VERSION 5.7 ;
BUSBITCHARS "[]" ;
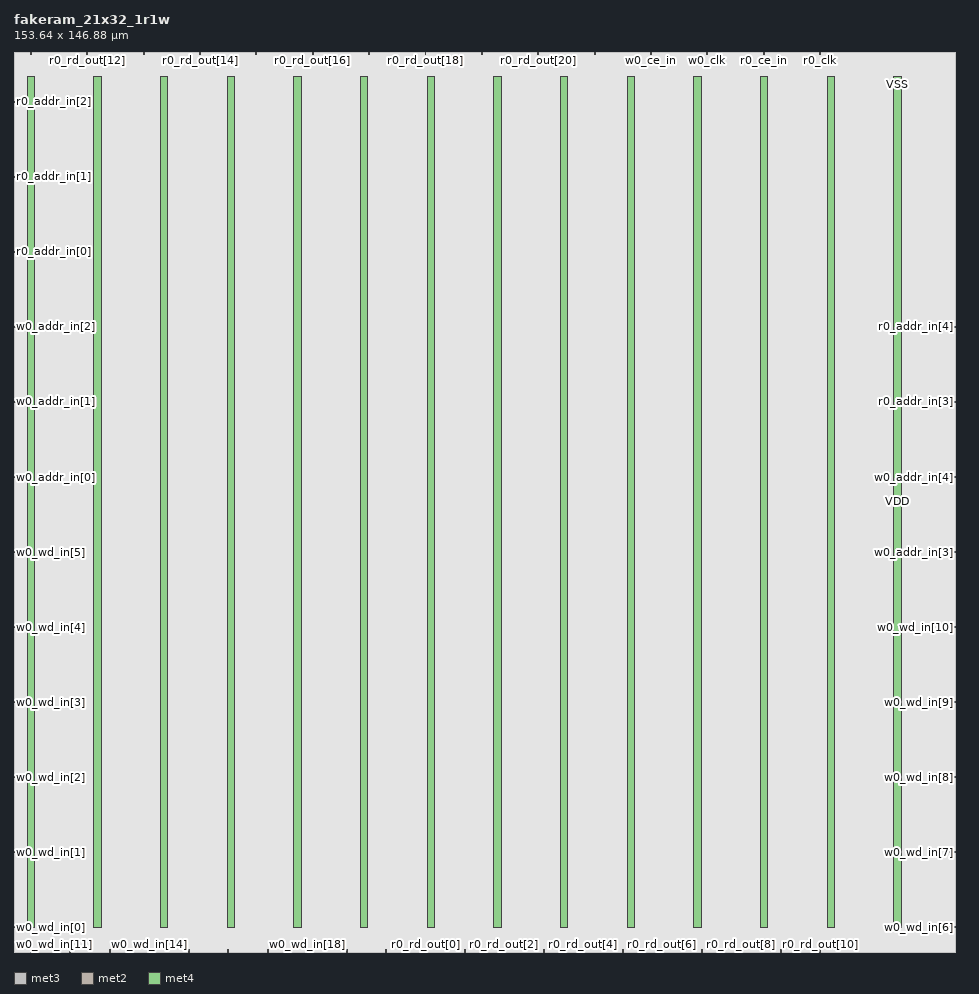
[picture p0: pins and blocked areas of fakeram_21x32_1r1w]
MACRO fakeram_21x32_1r1w
  FOREIGN fakeram_21x32_1r1w 0 0 ;
  SYMMETRY X Y R90 ;
  SIZE 153.640 BY 146.880 ;
  CLASS BLOCK ;
  PIN w0_wd_in[0]
    DIRECTION INPUT ;
    USE SIGNAL ;
    SHAPE ABUTMENT ;
    PORT
      LAYER met3 ;
      RECT 0.000 3.930 0.900 4.230 ;
    END
  END w0_wd_in[0]
  PIN w0_wd_in[1]
    DIRECTION INPUT ;
    USE SIGNAL ;
    SHAPE ABUTMENT ;
    PORT
      LAYER met3 ;
      RECT 0.000 16.170 0.900 16.470 ;
    END
  END w0_wd_in[1]
  PIN w0_wd_in[2]
    DIRECTION INPUT ;
    USE SIGNAL ;
    SHAPE ABUTMENT ;
    PORT
      LAYER met3 ;
      RECT 0.000 28.410 0.900 28.710 ;
    END
  END w0_wd_in[2]
  PIN w0_wd_in[3]
    DIRECTION INPUT ;
    USE SIGNAL ;
    SHAPE ABUTMENT ;
    PORT
      LAYER met3 ;
      RECT 0.000 40.650 0.900 40.950 ;
    END
  END w0_wd_in[3]
  PIN w0_wd_in[4]
    DIRECTION INPUT ;
    USE SIGNAL ;
    SHAPE ABUTMENT ;
    PORT
      LAYER met3 ;
      RECT 0.000 52.890 0.900 53.190 ;
    END
  END w0_wd_in[4]
  PIN w0_wd_in[5]
    DIRECTION INPUT ;
    USE SIGNAL ;
    SHAPE ABUTMENT ;
    PORT
      LAYER met3 ;
      RECT 0.000 65.130 0.900 65.430 ;
    END
  END w0_wd_in[5]
  PIN w0_wd_in[6]
    DIRECTION INPUT ;
    USE SIGNAL ;
    SHAPE ABUTMENT ;
    PORT
      LAYER met3 ;
      RECT 152.740 3.930 153.640 4.230 ;
    END
  END w0_wd_in[6]
  PIN w0_wd_in[7]
    DIRECTION INPUT ;
    USE SIGNAL ;
    SHAPE ABUTMENT ;
    PORT
      LAYER met3 ;
      RECT 152.740 16.170 153.640 16.470 ;
    END
  END w0_wd_in[7]
  PIN w0_wd_in[8]
    DIRECTION INPUT ;
    USE SIGNAL ;
    SHAPE ABUTMENT ;
    PORT
      LAYER met3 ;
      RECT 152.740 28.410 153.640 28.710 ;
    END
  END w0_wd_in[8]
  PIN w0_wd_in[9]
    DIRECTION INPUT ;
    USE SIGNAL ;
    SHAPE ABUTMENT ;
    PORT
      LAYER met3 ;
      RECT 152.740 40.650 153.640 40.950 ;
    END
  END w0_wd_in[9]
  PIN w0_wd_in[10]
    DIRECTION INPUT ;
    USE SIGNAL ;
    SHAPE ABUTMENT ;
    PORT
      LAYER met3 ;
      RECT 152.740 52.890 153.640 53.190 ;
    END
  END w0_wd_in[10]
  PIN w0_wd_in[11]
    DIRECTION OUTPUT ;
    USE SIGNAL ;
    SHAPE ABUTMENT ;
    PORT
      LAYER met2 ;
      RECT 2.690 0.000 2.830 0.420 ;
    END
  END w0_wd_in[11]
  PIN w0_wd_in[12]
    DIRECTION OUTPUT ;
    USE SIGNAL ;
    SHAPE ABUTMENT ;
    PORT
      LAYER met2 ;
      RECT 9.130 0.000 9.270 0.420 ;
    END
  END w0_wd_in[12]
  PIN w0_wd_in[13]
    DIRECTION OUTPUT ;
    USE SIGNAL ;
    SHAPE ABUTMENT ;
    PORT
      LAYER met2 ;
      RECT 15.570 0.000 15.710 0.420 ;
    END
  END w0_wd_in[13]
  PIN w0_wd_in[14]
    DIRECTION OUTPUT ;
    USE SIGNAL ;
    SHAPE ABUTMENT ;
    PORT
      LAYER met2 ;
      RECT 22.010 0.000 22.150 0.420 ;
    END
  END w0_wd_in[14]
  PIN w0_wd_in[15]
    DIRECTION OUTPUT ;
    USE SIGNAL ;
    SHAPE ABUTMENT ;
    PORT
      LAYER met2 ;
      RECT 28.450 0.000 28.590 0.420 ;
    END
  END w0_wd_in[15]
  PIN w0_wd_in[16]
    DIRECTION OUTPUT ;
    USE SIGNAL ;
    SHAPE ABUTMENT ;
    PORT
      LAYER met2 ;
      RECT 34.890 0.000 35.030 0.420 ;
    END
  END w0_wd_in[16]
  PIN w0_wd_in[17]
    DIRECTION OUTPUT ;
    USE SIGNAL ;
    SHAPE ABUTMENT ;
    PORT
      LAYER met2 ;
      RECT 41.330 0.000 41.470 0.420 ;
    END
  END w0_wd_in[17]
  PIN w0_wd_in[18]
    DIRECTION OUTPUT ;
    USE SIGNAL ;
    SHAPE ABUTMENT ;
    PORT
      LAYER met2 ;
      RECT 47.770 0.000 47.910 0.420 ;
    END
  END w0_wd_in[18]
  PIN w0_wd_in[19]
    DIRECTION OUTPUT ;
    USE SIGNAL ;
    SHAPE ABUTMENT ;
    PORT
      LAYER met2 ;
      RECT 54.210 0.000 54.350 0.420 ;
    END
  END w0_wd_in[19]
  PIN w0_wd_in[20]
    DIRECTION OUTPUT ;
    USE SIGNAL ;
    SHAPE ABUTMENT ;
    PORT
      LAYER met2 ;
      RECT 60.650 0.000 60.790 0.420 ;
    END
  END w0_wd_in[20]
  PIN r0_rd_out[0]
    DIRECTION OUTPUT ;
    USE SIGNAL ;
    SHAPE ABUTMENT ;
    PORT
      LAYER met2 ;
      RECT 67.090 0.000 67.230 0.420 ;
    END
  END r0_rd_out[0]
  PIN r0_rd_out[1]
    DIRECTION OUTPUT ;
    USE SIGNAL ;
    SHAPE ABUTMENT ;
    PORT
      LAYER met2 ;
      RECT 73.530 0.000 73.670 0.420 ;
    END
  END r0_rd_out[1]
  PIN r0_rd_out[2]
    DIRECTION OUTPUT ;
    USE SIGNAL ;
    SHAPE ABUTMENT ;
    PORT
      LAYER met2 ;
      RECT 79.970 0.000 80.110 0.420 ;
    END
  END r0_rd_out[2]
  PIN r0_rd_out[3]
    DIRECTION OUTPUT ;
    USE SIGNAL ;
    SHAPE ABUTMENT ;
    PORT
      LAYER met2 ;
      RECT 86.410 0.000 86.550 0.420 ;
    END
  END r0_rd_out[3]
  PIN r0_rd_out[4]
    DIRECTION OUTPUT ;
    USE SIGNAL ;
    SHAPE ABUTMENT ;
    PORT
      LAYER met2 ;
      RECT 92.850 0.000 92.990 0.420 ;
    END
  END r0_rd_out[4]
  PIN r0_rd_out[5]
    DIRECTION OUTPUT ;
    USE SIGNAL ;
    SHAPE ABUTMENT ;
    PORT
      LAYER met2 ;
      RECT 99.290 0.000 99.430 0.420 ;
    END
  END r0_rd_out[5]
  PIN r0_rd_out[6]
    DIRECTION OUTPUT ;
    USE SIGNAL ;
    SHAPE ABUTMENT ;
    PORT
      LAYER met2 ;
      RECT 105.730 0.000 105.870 0.420 ;
    END
  END r0_rd_out[6]
  PIN r0_rd_out[7]
    DIRECTION OUTPUT ;
    USE SIGNAL ;
    SHAPE ABUTMENT ;
    PORT
      LAYER met2 ;
      RECT 112.170 0.000 112.310 0.420 ;
    END
  END r0_rd_out[7]
  PIN r0_rd_out[8]
    DIRECTION OUTPUT ;
    USE SIGNAL ;
    SHAPE ABUTMENT ;
    PORT
      LAYER met2 ;
      RECT 118.610 0.000 118.750 0.420 ;
    END
  END r0_rd_out[8]
  PIN r0_rd_out[9]
    DIRECTION OUTPUT ;
    USE SIGNAL ;
    SHAPE ABUTMENT ;
    PORT
      LAYER met2 ;
      RECT 125.050 0.000 125.190 0.420 ;
    END
  END r0_rd_out[9]
  PIN r0_rd_out[10]
    DIRECTION OUTPUT ;
    USE SIGNAL ;
    SHAPE ABUTMENT ;
    PORT
      LAYER met2 ;
      RECT 131.490 0.000 131.630 0.420 ;
    END
  END r0_rd_out[10]
  PIN r0_rd_out[11]
    DIRECTION OUTPUT ;
    USE SIGNAL ;
    SHAPE ABUTMENT ;
    PORT
      LAYER met2 ;
      RECT 2.690 146.460 2.830 146.880 ;
    END
  END r0_rd_out[11]
  PIN r0_rd_out[12]
    DIRECTION OUTPUT ;
    USE SIGNAL ;
    SHAPE ABUTMENT ;
    PORT
      LAYER met2 ;
      RECT 11.890 146.460 12.030 146.880 ;
    END
  END r0_rd_out[12]
  PIN r0_rd_out[13]
    DIRECTION OUTPUT ;
    USE SIGNAL ;
    SHAPE ABUTMENT ;
    PORT
      LAYER met2 ;
      RECT 21.090 146.460 21.230 146.880 ;
    END
  END r0_rd_out[13]
  PIN r0_rd_out[14]
    DIRECTION OUTPUT ;
    USE SIGNAL ;
    SHAPE ABUTMENT ;
    PORT
      LAYER met2 ;
      RECT 30.290 146.460 30.430 146.880 ;
    END
  END r0_rd_out[14]
  PIN r0_rd_out[15]
    DIRECTION OUTPUT ;
    USE SIGNAL ;
    SHAPE ABUTMENT ;
    PORT
      LAYER met2 ;
      RECT 39.490 146.460 39.630 146.880 ;
    END
  END r0_rd_out[15]
  PIN r0_rd_out[16]
    DIRECTION OUTPUT ;
    USE SIGNAL ;
    SHAPE ABUTMENT ;
    PORT
      LAYER met2 ;
      RECT 48.690 146.460 48.830 146.880 ;
    END
  END r0_rd_out[16]
  PIN r0_rd_out[17]
    DIRECTION OUTPUT ;
    USE SIGNAL ;
    SHAPE ABUTMENT ;
    PORT
      LAYER met2 ;
      RECT 57.890 146.460 58.030 146.880 ;
    END
  END r0_rd_out[17]
  PIN r0_rd_out[18]
    DIRECTION OUTPUT ;
    USE SIGNAL ;
    SHAPE ABUTMENT ;
    PORT
      LAYER met2 ;
      RECT 67.090 146.460 67.230 146.880 ;
    END
  END r0_rd_out[18]
  PIN r0_rd_out[19]
    DIRECTION OUTPUT ;
    USE SIGNAL ;
    SHAPE ABUTMENT ;
    PORT
      LAYER met2 ;
      RECT 76.290 146.460 76.430 146.880 ;
    END
  END r0_rd_out[19]
  PIN r0_rd_out[20]
    DIRECTION OUTPUT ;
    USE SIGNAL ;
    SHAPE ABUTMENT ;
    PORT
      LAYER met2 ;
      RECT 85.490 146.460 85.630 146.880 ;
    END
  END r0_rd_out[20]
  PIN w0_addr_in[0]
    DIRECTION INPUT ;
    USE SIGNAL ;
    SHAPE ABUTMENT ;
    PORT
      LAYER met3 ;
      RECT 0.000 77.370 0.900 77.670 ;
    END
  END w0_addr_in[0]
  PIN w0_addr_in[1]
    DIRECTION INPUT ;
    USE SIGNAL ;
    SHAPE ABUTMENT ;
    PORT
      LAYER met3 ;
      RECT 0.000 89.610 0.900 89.910 ;
    END
  END w0_addr_in[1]
  PIN w0_addr_in[2]
    DIRECTION INPUT ;
    USE SIGNAL ;
    SHAPE ABUTMENT ;
    PORT
      LAYER met3 ;
      RECT 0.000 101.850 0.900 102.150 ;
    END
  END w0_addr_in[2]
  PIN w0_addr_in[3]
    DIRECTION INPUT ;
    USE SIGNAL ;
    SHAPE ABUTMENT ;
    PORT
      LAYER met3 ;
      RECT 152.740 65.130 153.640 65.430 ;
    END
  END w0_addr_in[3]
  PIN w0_addr_in[4]
    DIRECTION INPUT ;
    USE SIGNAL ;
    SHAPE ABUTMENT ;
    PORT
      LAYER met3 ;
      RECT 152.740 77.370 153.640 77.670 ;
    END
  END w0_addr_in[4]
  PIN r0_addr_in[0]
    DIRECTION INPUT ;
    USE SIGNAL ;
    SHAPE ABUTMENT ;
    PORT
      LAYER met3 ;
      RECT 0.000 114.090 0.900 114.390 ;
    END
  END r0_addr_in[0]
  PIN r0_addr_in[1]
    DIRECTION INPUT ;
    USE SIGNAL ;
    SHAPE ABUTMENT ;
    PORT
      LAYER met3 ;
      RECT 0.000 126.330 0.900 126.630 ;
    END
  END r0_addr_in[1]
  PIN r0_addr_in[2]
    DIRECTION INPUT ;
    USE SIGNAL ;
    SHAPE ABUTMENT ;
    PORT
      LAYER met3 ;
      RECT 0.000 138.570 0.900 138.870 ;
    END
  END r0_addr_in[2]
  PIN r0_addr_in[3]
    DIRECTION INPUT ;
    USE SIGNAL ;
    SHAPE ABUTMENT ;
    PORT
      LAYER met3 ;
      RECT 152.740 89.610 153.640 89.910 ;
    END
  END r0_addr_in[3]
  PIN r0_addr_in[4]
    DIRECTION INPUT ;
    USE SIGNAL ;
    SHAPE ABUTMENT ;
    PORT
      LAYER met3 ;
      RECT 152.740 101.850 153.640 102.150 ;
    END
  END r0_addr_in[4]
  PIN w0_we_in
    DIRECTION INPUT ;
    USE SIGNAL ;
    SHAPE ABUTMENT ;
    PORT
      LAYER met2 ;
      RECT 94.690 146.460 94.830 146.880 ;
    END
  END w0_we_in
  PIN w0_ce_in
    DIRECTION INPUT ;
    USE SIGNAL ;
    SHAPE ABUTMENT ;
    PORT
      LAYER met2 ;
      RECT 103.890 146.460 104.030 146.880 ;
    END
  END w0_ce_in
  PIN w0_clk
    DIRECTION INPUT ;
    USE SIGNAL ;
    SHAPE ABUTMENT ;
    PORT
      LAYER met2 ;
      RECT 113.090 146.460 113.230 146.880 ;
    END
  END w0_clk
  PIN r0_ce_in
    DIRECTION INPUT ;
    USE SIGNAL ;
    SHAPE ABUTMENT ;
    PORT
      LAYER met2 ;
      RECT 122.290 146.460 122.430 146.880 ;
    END
  END r0_ce_in
  PIN r0_clk
    DIRECTION INPUT ;
    USE SIGNAL ;
    SHAPE ABUTMENT ;
    PORT
      LAYER met2 ;
      RECT 131.490 146.460 131.630 146.880 ;
    END
  END r0_clk
  PIN VSS
    DIRECTION INOUT ;
    USE GROUND ;
    PORT
      LAYER met4 ;
      RECT 2.160 4.080 3.360 142.800 ;
      RECT 13.040 4.080 14.240 142.800 ;
      RECT 23.920 4.080 25.120 142.800 ;
      RECT 34.800 4.080 36.000 142.800 ;
      RECT 45.680 4.080 46.880 142.800 ;
      RECT 56.560 4.080 57.760 142.800 ;
      RECT 67.440 4.080 68.640 142.800 ;
      RECT 78.320 4.080 79.520 142.800 ;
      RECT 89.200 4.080 90.400 142.800 ;
      RECT 100.080 4.080 101.280 142.800 ;
      RECT 110.960 4.080 112.160 142.800 ;
      RECT 121.840 4.080 123.040 142.800 ;
      RECT 132.720 4.080 133.920 142.800 ;
      RECT 143.600 4.080 144.800 142.800 ;
    END
  END VSS
  PIN VDD
    DIRECTION INOUT ;
    USE POWER ;
    PORT
      LAYER met4 ;
      RECT 2.160 4.080 3.360 142.800 ;
      RECT 13.040 4.080 14.240 142.800 ;
      RECT 23.920 4.080 25.120 142.800 ;
      RECT 34.800 4.080 36.000 142.800 ;
      RECT 45.680 4.080 46.880 142.800 ;
      RECT 56.560 4.080 57.760 142.800 ;
      RECT 67.440 4.080 68.640 142.800 ;
      RECT 78.320 4.080 79.520 142.800 ;
      RECT 89.200 4.080 90.400 142.800 ;
      RECT 100.080 4.080 101.280 142.800 ;
      RECT 110.960 4.080 112.160 142.800 ;
      RECT 121.840 4.080 123.040 142.800 ;
      RECT 132.720 4.080 133.920 142.800 ;
      RECT 143.600 4.080 144.800 142.800 ;
    END
  END VDD
  OBS
    LAYER met1 ;
    RECT 0 0 153.640 146.880 ;
    LAYER met2 ;
    RECT 0 0 153.640 146.880 ;
    LAYER met3 ;
    RECT 0 0 153.640 146.880 ;
    LAYER met4 ;
    RECT 0 0 153.640 146.880 ;
  END
END fakeram_21x32_1r1w

END LIBRARY
